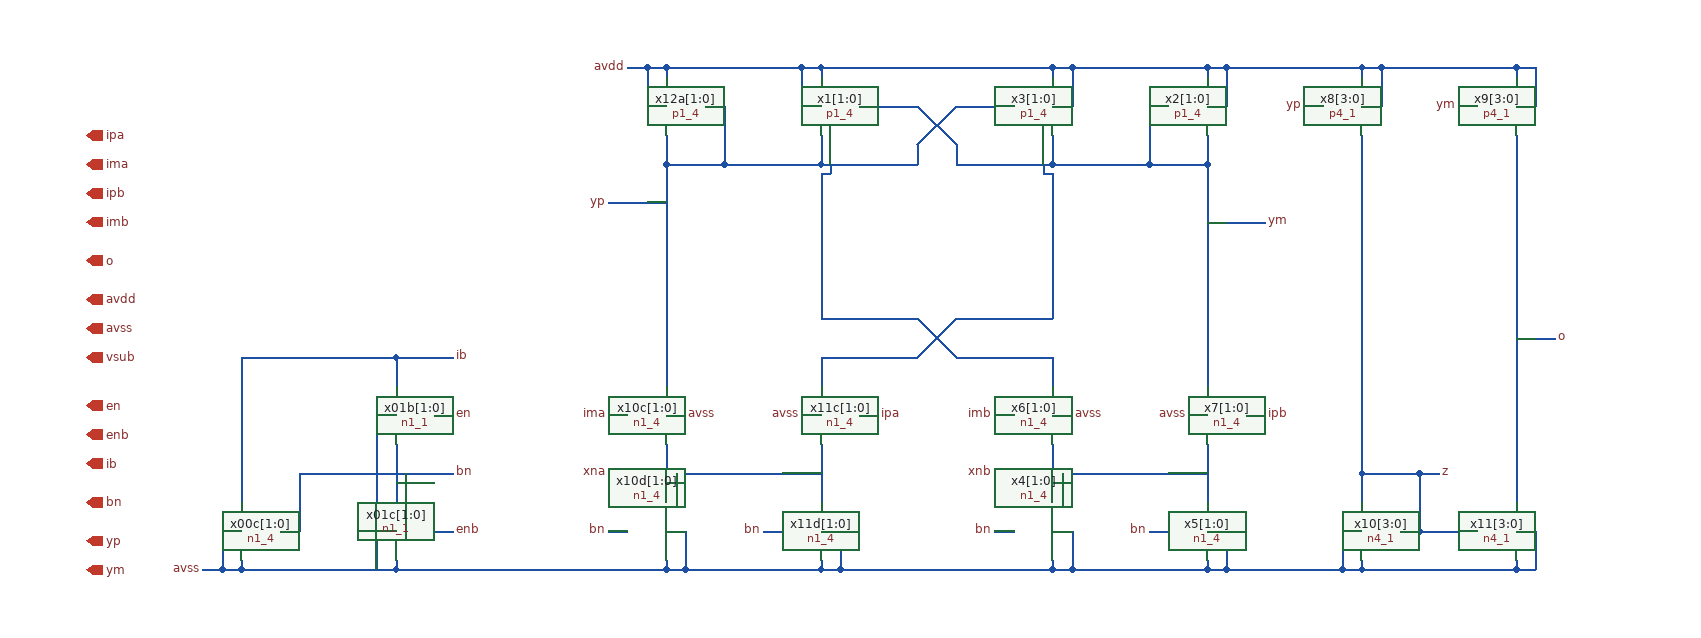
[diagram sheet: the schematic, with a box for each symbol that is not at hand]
v {xschem version=3.4.8RC file_version=1.3}
G {}
K {}
V {}
S {}
F {}
E {}
N 200 -200 220 -200 { lab=avss}
N 200 -200 200 -160 { lab=avss}
N 200 -160 220 -160 { lab=avss}
N 220 -170 220 -160 { lab=avss}
N 180 -160 200 -160 { lab=avss}
N 660 -170 660 -160 { lab=avss}
N 680 -200 680 -160 { lab=avss}
N 660 -160 680 -160 { lab=avss}
N 660 -200 680 -200 { lab=avss}
N 600 -200 620 -200 { lab=bn}
N 820 -170 820 -160 { lab=avss}
N 840 -200 840 -160 { lab=avss}
N 820 -160 840 -160 { lab=avss}
N 820 -200 840 -200 { lab=avss}
N 760 -200 780 -200 { lab=bn}
N 680 -160 820 -160 { lab=avss}
N 820 -290 820 -230 { lab=xna}
N 660 -290 660 -230 { lab=xna}
N 600 -260 820 -260 { lab=xna}
N 670 -260 670 -250 { lab=xna}
N 660 -250 670 -250 { lab=xna}
N 660 -320 680 -320 { lab=avss}
N 800 -320 820 -320 { lab=avss}
N 660 -680 660 -670 { lab=avdd}
N 640 -680 660 -680 { lab=avdd}
N 640 -680 640 -640 { lab=avdd}
N 640 -640 660 -640 { lab=avdd}
N 860 -320 880 -320 { lab=ipa}
N 600 -320 620 -320 { lab=ima}
N 260 -200 280 -200 { lab=bn}
N 220 -160 380 -160 { lab=avss}
N 280 -260 280 -200 { lab=bn}
N 220 -380 220 -230 { lab=ib}
N 280 -260 440 -260 { lab=bn}
N 380 -290 380 -230 { lab=bn}
N 380 -170 380 -160 { lab=avss}
N 420 -200 440 -200 { lab=enb}
N 420 -320 440 -320 { lab=en}
N 380 -380 380 -350 { lab=ib}
N 360 -320 380 -320 { lab=avss}
N 360 -320 360 -200 { lab=avss}
N 360 -200 380 -200 { lab=avss}
N 360 -200 360 -160 { lab=avss}
N 390 -260 390 -250 { lab=bn}
N 380 -250 390 -250 { lab=bn}
N 220 -380 380 -380 { lab=ib}
N 380 -380 440 -380 { lab=ib}
N 380 -160 660 -160 { lab=avss}
N 820 -680 820 -670 { lab=avdd}
N 800 -680 820 -680 { lab=avdd}
N 800 -680 800 -640 { lab=avdd}
N 800 -640 820 -640 { lab=avdd}
N 700 -640 720 -640 {
lab=yp}
N 720 -640 720 -580 {
lab=yp}
N 660 -580 720 -580 {
lab=yp}
N 660 -610 660 -580 {
lab=yp}
N 820 -610 820 -580 {
lab=yp}
N 720 -580 820 -580 {
lab=yp}
N 1220 -680 1220 -670 { lab=avdd}
N 1220 -680 1240 -680 { lab=avdd}
N 1240 -680 1240 -640 { lab=avdd}
N 1220 -640 1240 -640 { lab=avdd}
N 1060 -680 1060 -670 { lab=avdd}
N 1060 -680 1080 -680 { lab=avdd}
N 1080 -680 1080 -640 { lab=avdd}
N 1060 -640 1080 -640 { lab=avdd}
N 1160 -640 1180 -640 {
lab=ym}
N 1160 -640 1160 -580 {
lab=ym}
N 1160 -580 1220 -580 {
lab=ym}
N 1220 -610 1220 -580 {
lab=ym}
N 1060 -610 1060 -580 {
lab=ym}
N 1060 -580 1160 -580 {
lab=ym}
N 660 -680 800 -680 {
lab=avdd}
N 1080 -680 1220 -680 {
lab=avdd}
N 920 -640 960 -600 {
lab=ym}
N 920 -600 960 -640 {
lab=yp}
N 920 -600 920 -580 {
lab=yp}
N 960 -600 960 -580 {
lab=ym}
N 1060 -170 1060 -160 { lab=avss}
N 1080 -200 1080 -160 { lab=avss}
N 1060 -160 1080 -160 { lab=avss}
N 1060 -200 1080 -200 { lab=avss}
N 1000 -200 1020 -200 { lab=bn}
N 1220 -170 1220 -160 { lab=avss}
N 1240 -200 1240 -160 { lab=avss}
N 1220 -160 1240 -160 { lab=avss}
N 1220 -200 1240 -200 { lab=avss}
N 1160 -200 1180 -200 { lab=bn}
N 1080 -160 1220 -160 { lab=avss}
N 1220 -290 1220 -230 { lab=xnb}
N 1060 -290 1060 -230 { lab=xnb}
N 1000 -260 1220 -260 { lab=xnb}
N 1070 -260 1070 -250 { lab=xnb}
N 1060 -250 1070 -250 { lab=xnb}
N 1060 -320 1080 -320 { lab=avss}
N 1200 -320 1220 -320 { lab=avss}
N 1260 -320 1280 -320 { lab=ipb}
N 1000 -320 1020 -320 { lab=ipb}
N 840 -160 1060 -160 {
lab=avss}
N 960 -640 1020 -640 {
lab=yp}
N 860 -640 920 -640 {
lab=ym}
N 820 -580 920 -580 {
lab=yp}
N 960 -580 1060 -580 {
lab=ym}
N 820 -680 1060 -680 {
lab=avdd}
N 660 -580 660 -350 {
lab=yp}
N 1220 -580 1220 -350 {
lab=ym}
N 1060 -380 1060 -350 {
lab=yp}
N 960 -380 1060 -380 {
lab=yp}
N 920 -420 960 -380 {
lab=yp}
N 820 -420 920 -420 {
lab=yp}
N 820 -570 820 -420 {
lab=yp}
N 820 -570 830 -570 {
lab=yp}
N 830 -580 830 -570 {
lab=yp}
N 820 -380 820 -350 {
lab=ym}
N 820 -380 920 -380 {
lab=ym}
N 920 -380 960 -420 {
lab=ym}
N 960 -420 1060 -420 {
lab=ym}
N 1060 -570 1060 -420 {
lab=ym}
N 1050 -570 1060 -570 {
lab=ym}
N 1050 -580 1050 -570 {
lab=ym}
N 620 -680 640 -680 {
lab=avdd}
N 1380 -680 1380 -670 { lab=avdd}
N 1380 -680 1400 -680 { lab=avdd}
N 1400 -680 1400 -640 { lab=avdd}
N 1380 -640 1400 -640 { lab=avdd}
N 1320 -640 1340 -640 {
lab=yp}
N 1540 -680 1540 -670 { lab=avdd}
N 1540 -680 1560 -680 { lab=avdd}
N 1560 -680 1560 -640 { lab=avdd}
N 1540 -640 1560 -640 { lab=avdd}
N 1480 -640 1500 -640 {
lab=ym}
N 1380 -170 1380 -160 { lab=avss}
N 1360 -200 1360 -160 { lab=avss}
N 1360 -160 1380 -160 { lab=avss}
N 1360 -200 1380 -200 { lab=avss}
N 1540 -170 1540 -160 { lab=avss}
N 1560 -200 1560 -160 { lab=avss}
N 1540 -160 1560 -160 { lab=avss}
N 1540 -200 1560 -200 { lab=avss}
N 1380 -160 1540 -160 {
lab=avss}
N 1420 -200 1440 -200 {
lab=z}
N 1440 -260 1440 -200 {
lab=z}
N 1380 -260 1440 -260 {
lab=z}
N 1380 -260 1380 -230 {
lab=z}
N 1380 -610 1380 -260 {
lab=z}
N 1400 -680 1540 -680 {
lab=avdd}
N 1540 -610 1540 -230 {
lab=o}
N 1440 -200 1500 -200 {
lab=z}
N 1240 -680 1380 -680 {
lab=avdd}
N 1240 -160 1360 -160 {
lab=avss}
N 1540 -400 1580 -400 {
lab=o}
N 600 -540 620 -540 { lab=yp}
N 620 -540 660 -540 {
lab=yp}
N 1260 -520 1280 -520 { lab=ym}
N 1220 -520 1260 -520 {
lab=ym}
N 1440 -260 1460 -260 { lab=z}
C {devices/title.sym} 160 -40 0 0 {name=l6 author="Luis Henrique Rodovalho"}
C {devices/iopin.sym} 60 -440 2 1 {name=pavdd lab=avdd}
C {devices/iopin.sym} 60 -410 2 1 {name=pavss lab=avss}
C {devices/iopin.sym} 60 -610 2 1 {name=pip lab=ipa}
C {devices/iopin.sym} 60 -580 2 1 {name=pim lab=ima}
C {devices/iopin.sym} 60 -480 2 1 {name=po lab=o}
C {devices/lab_pin.sym} 440 -260 2 0 {name=l11 sig_type=std_logic lab=bn}
C {devices/lab_pin.sym} 180 -160 2 1 {name=lavss0 sig_type=std_logic lab=avss}
C {n1_4.sym} 640 -200 0 0 {name=x10d[1:0]}
C {devices/lab_pin.sym} 600 -200 2 1 {name=l24 sig_type=std_logic lab=bn}
C {n1_4.sym} 800 -200 0 0 {name=x11d[1:0]}
C {devices/lab_pin.sym} 760 -200 2 1 {name=l25 sig_type=std_logic lab=bn}
C {n1_4.sym} 640 -320 0 0 {name=x10c[1:0]}
C {n1_4.sym} 840 -320 0 1 {name=x11c[1:0]}
C {devices/lab_pin.sym} 600 -260 2 1 {name=lxn sig_type=std_logic lab=xna}
C {devices/lab_pin.sym} 680 -320 2 0 {name=lavss2 sig_type=std_logic lab=avss}
C {devices/lab_pin.sym} 800 -320 2 1 {name=lavss3 sig_type=std_logic lab=avss}
C {p1_4.sym} 680 -640 0 1 {name=x12a[1:0]}
C {devices/lab_pin.sym} 620 -680 2 1 {name=lavdd0 sig_type=std_logic lab=avdd}
C {devices/lab_pin.sym} 1580 -400 2 0 {name=l3 sig_type=std_logic lab=o}
C {devices/lab_pin.sym} 880 -320 2 0 {name=l7 sig_type=std_logic lab=ipa}
C {devices/lab_pin.sym} 600 -320 2 1 {name=l8 sig_type=std_logic lab=ima}
C {n1_1.sym} 400 -200 0 1 {name=x01c[1:0]}
C {n1_1.sym} 400 -320 0 1 {name=x01b[1:0]}
C {n1_4.sym} 240 -200 0 1 {name=x00c[1:0]}
C {devices/lab_pin.sym} 440 -200 2 0 {name=l46 sig_type=std_logic lab=enb}
C {devices/lab_pin.sym} 440 -320 2 0 {name=l47 sig_type=std_logic lab=en}
C {devices/lab_pin.sym} 440 -380 2 0 {name=l9 sig_type=std_logic lab=ib}
C {devices/iopin.sym} 60 -270 2 1 {name=pbnb lab=ib}
C {devices/iopin.sym} 60 -230 2 1 {name=pbna lab=bn}
C {devices/iopin.sym} 60 -190 2 1 {name=pypp lab=yp}
C {devices/iopin.sym} 60 -160 2 1 {name=pypm lab=ym}
C {devices/iopin.sym} 60 -380 2 1 {name=pvsub lab=vsub}
C {devices/iopin.sym} 60 -330 2 1 {name=pen lab=en}
C {devices/iopin.sym} 60 -300 2 1 {name=penb lab=enb}
C {p1_4.sym} 840 -640 0 1 {name=x1[1:0]}
C {p1_4.sym} 1200 -640 0 0 {name=x2[1:0]}
C {p1_4.sym} 1040 -640 0 0 {name=x3[1:0]}
C {n1_4.sym} 1040 -200 0 0 {name=x4[1:0]}
C {devices/lab_pin.sym} 1000 -200 2 1 {name=l1 sig_type=std_logic lab=bn}
C {n1_4.sym} 1200 -200 0 0 {name=x5[1:0]}
C {devices/lab_pin.sym} 1160 -200 2 1 {name=l2 sig_type=std_logic lab=bn}
C {n1_4.sym} 1040 -320 0 0 {name=x6[1:0]}
C {n1_4.sym} 1240 -320 0 1 {name=x7[1:0]}
C {devices/lab_pin.sym} 1000 -260 2 1 {name=lxn1 sig_type=std_logic lab=xnb}
C {devices/lab_pin.sym} 1080 -320 2 0 {name=lavss1 sig_type=std_logic lab=avss}
C {devices/lab_pin.sym} 1200 -320 2 1 {name=lavss4 sig_type=std_logic lab=avss}
C {devices/lab_pin.sym} 1280 -320 2 0 {name=l4 sig_type=std_logic lab=ipb}
C {devices/lab_pin.sym} 1000 -320 2 1 {name=l5 sig_type=std_logic lab=imb}
C {p4_1.sym} 1360 -640 0 0 {name=x8[3:0]}
C {p4_1.sym} 1520 -640 0 0 {name=x9[3:0]}
C {n4_1.sym} 1400 -200 0 1 {name=x10[3:0]}
C {n4_1.sym} 1520 -200 0 0 {name=x11[3:0]}
C {devices/lab_pin.sym} 600 -540 2 1 {name=l10 sig_type=std_logic lab=yp}
C {devices/lab_pin.sym} 1280 -520 2 0 {name=l12 sig_type=std_logic lab=ym}
C {devices/lab_pin.sym} 1320 -640 2 1 {name=lavdd1 sig_type=std_logic lab=yp}
C {devices/lab_pin.sym} 1480 -640 2 1 {name=lavdd2 sig_type=std_logic lab=ym}
C {devices/lab_pin.sym} 1460 -260 2 0 {name=l13 sig_type=std_logic lab=z}
C {devices/iopin.sym} 60 -550 2 1 {name=pip1 lab=ipb}
C {devices/iopin.sym} 60 -520 2 1 {name=pim1 lab=imb}
